VERSION 5.7 ;
  NOWIREEXTENSIONATPIN ON ;
  DIVIDERCHAR "/" ;
  BUSBITCHARS "[]" ;
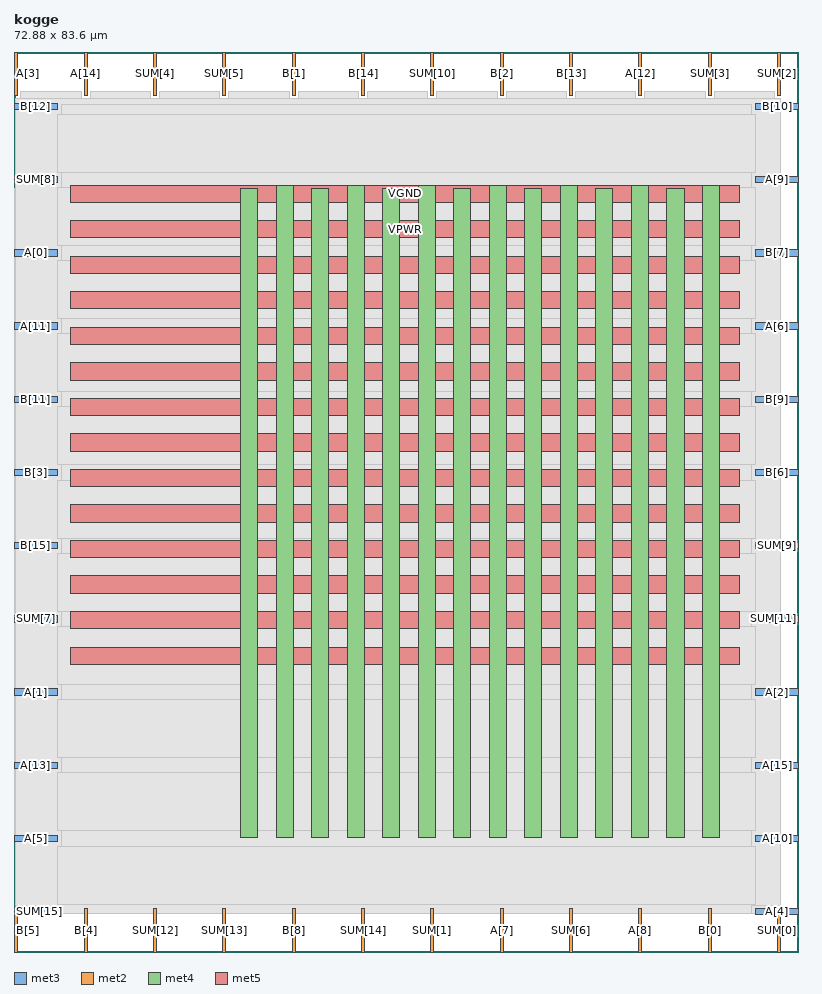
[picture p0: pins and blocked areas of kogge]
MACRO kogge
  CLASS BLOCK ;
  FOREIGN kogge ;
  ORIGIN 0.000 0.000 ;
  SIZE 72.880 BY 83.600 ;
  PIN A[0]
    DIRECTION INPUT ;
    USE SIGNAL ;
    ANTENNAGATEAREA 0.196500 ;
    PORT
      LAYER met3 ;
        RECT 0.000 64.640 4.000 65.240 ;
    END
  END A[0]
  PIN A[10]
    DIRECTION INPUT ;
    USE SIGNAL ;
    ANTENNAGATEAREA 0.213000 ;
    PORT
      LAYER met3 ;
        RECT 68.880 10.240 72.880 10.840 ;
    END
  END A[10]
  PIN A[11]
    DIRECTION INPUT ;
    USE SIGNAL ;
    ANTENNAGATEAREA 0.213000 ;
    PORT
      LAYER met3 ;
        RECT 0.000 57.840 4.000 58.440 ;
    END
  END A[11]
  PIN A[12]
    DIRECTION INPUT ;
    USE SIGNAL ;
    ANTENNAGATEAREA 0.213000 ;
    PORT
      LAYER met2 ;
        RECT 58.050 79.600 58.330 83.600 ;
    END
  END A[12]
  PIN A[13]
    DIRECTION INPUT ;
    USE SIGNAL ;
    ANTENNAGATEAREA 0.213000 ;
    PORT
      LAYER met3 ;
        RECT 0.000 17.040 4.000 17.640 ;
    END
  END A[13]
  PIN A[14]
    DIRECTION INPUT ;
    USE SIGNAL ;
    ANTENNAGATEAREA 0.196500 ;
    PORT
      LAYER met2 ;
        RECT 6.530 79.600 6.810 83.600 ;
    END
  END A[14]
  PIN A[15]
    DIRECTION INPUT ;
    USE SIGNAL ;
    ANTENNAGATEAREA 0.196500 ;
    PORT
      LAYER met3 ;
        RECT 68.880 17.040 72.880 17.640 ;
    END
  END A[15]
  PIN A[1]
    DIRECTION INPUT ;
    USE SIGNAL ;
    ANTENNAGATEAREA 0.196500 ;
    PORT
      LAYER met3 ;
        RECT 0.000 23.840 4.000 24.440 ;
    END
  END A[1]
  PIN A[2]
    DIRECTION INPUT ;
    USE SIGNAL ;
    ANTENNAGATEAREA 0.213000 ;
    PORT
      LAYER met3 ;
        RECT 68.880 23.840 72.880 24.440 ;
    END
  END A[2]
  PIN A[3]
    DIRECTION INPUT ;
    USE SIGNAL ;
    ANTENNAGATEAREA 0.213000 ;
    PORT
      LAYER met2 ;
        RECT 0.090 79.600 0.370 83.600 ;
    END
  END A[3]
  PIN A[4]
    DIRECTION INPUT ;
    USE SIGNAL ;
    ANTENNAGATEAREA 0.213000 ;
    PORT
      LAYER met3 ;
        RECT 68.880 3.440 72.880 4.040 ;
    END
  END A[4]
  PIN A[5]
    DIRECTION INPUT ;
    USE SIGNAL ;
    ANTENNAGATEAREA 0.213000 ;
    PORT
      LAYER met3 ;
        RECT 0.000 10.240 4.000 10.840 ;
    END
  END A[5]
  PIN A[6]
    DIRECTION INPUT ;
    USE SIGNAL ;
    ANTENNAGATEAREA 0.213000 ;
    PORT
      LAYER met3 ;
        RECT 68.880 57.840 72.880 58.440 ;
    END
  END A[6]
  PIN A[7]
    DIRECTION INPUT ;
    USE SIGNAL ;
    ANTENNAGATEAREA 0.213000 ;
    PORT
      LAYER met2 ;
        RECT 45.170 0.000 45.450 4.000 ;
    END
  END A[7]
  PIN A[8]
    DIRECTION INPUT ;
    USE SIGNAL ;
    ANTENNAGATEAREA 0.213000 ;
    PORT
      LAYER met2 ;
        RECT 58.050 0.000 58.330 4.000 ;
    END
  END A[8]
  PIN A[9]
    DIRECTION INPUT ;
    USE SIGNAL ;
    ANTENNAGATEAREA 0.213000 ;
    PORT
      LAYER met3 ;
        RECT 68.880 71.440 72.880 72.040 ;
    END
  END A[9]
  PIN B[0]
    DIRECTION INPUT ;
    USE SIGNAL ;
    ANTENNAGATEAREA 0.196500 ;
    PORT
      LAYER met2 ;
        RECT 64.490 0.000 64.770 4.000 ;
    END
  END B[0]
  PIN B[10]
    DIRECTION INPUT ;
    USE SIGNAL ;
    ANTENNAGATEAREA 0.213000 ;
    PORT
      LAYER met3 ;
        RECT 68.880 78.240 72.880 78.840 ;
    END
  END B[10]
  PIN B[11]
    DIRECTION INPUT ;
    USE SIGNAL ;
    ANTENNAGATEAREA 0.213000 ;
    PORT
      LAYER met3 ;
        RECT 0.000 51.040 4.000 51.640 ;
    END
  END B[11]
  PIN B[12]
    DIRECTION INPUT ;
    USE SIGNAL ;
    ANTENNAGATEAREA 0.213000 ;
    PORT
      LAYER met3 ;
        RECT 0.000 78.240 4.000 78.840 ;
    END
  END B[12]
  PIN B[13]
    DIRECTION INPUT ;
    USE SIGNAL ;
    ANTENNAGATEAREA 0.213000 ;
    PORT
      LAYER met2 ;
        RECT 51.610 79.600 51.890 83.600 ;
    END
  END B[13]
  PIN B[14]
    DIRECTION INPUT ;
    USE SIGNAL ;
    ANTENNAGATEAREA 0.196500 ;
    PORT
      LAYER met2 ;
        RECT 32.290 79.600 32.570 83.600 ;
    END
  END B[14]
  PIN B[15]
    DIRECTION INPUT ;
    USE SIGNAL ;
    ANTENNAGATEAREA 0.196500 ;
    PORT
      LAYER met3 ;
        RECT 0.000 37.440 4.000 38.040 ;
    END
  END B[15]
  PIN B[1]
    DIRECTION INPUT ;
    USE SIGNAL ;
    ANTENNAGATEAREA 0.126000 ;
    PORT
      LAYER met2 ;
        RECT 25.850 79.600 26.130 83.600 ;
    END
  END B[1]
  PIN B[2]
    DIRECTION INPUT ;
    USE SIGNAL ;
    ANTENNAGATEAREA 0.213000 ;
    PORT
      LAYER met2 ;
        RECT 45.170 79.600 45.450 83.600 ;
    END
  END B[2]
  PIN B[3]
    DIRECTION INPUT ;
    USE SIGNAL ;
    ANTENNAGATEAREA 0.213000 ;
    PORT
      LAYER met3 ;
        RECT 0.000 44.240 4.000 44.840 ;
    END
  END B[3]
  PIN B[4]
    DIRECTION INPUT ;
    USE SIGNAL ;
    ANTENNAGATEAREA 0.213000 ;
    PORT
      LAYER met2 ;
        RECT 6.530 0.000 6.810 4.000 ;
    END
  END B[4]
  PIN B[5]
    DIRECTION INPUT ;
    USE SIGNAL ;
    ANTENNAGATEAREA 0.213000 ;
    PORT
      LAYER met2 ;
        RECT 0.090 0.000 0.370 4.000 ;
    END
  END B[5]
  PIN B[6]
    DIRECTION INPUT ;
    USE SIGNAL ;
    ANTENNAGATEAREA 0.213000 ;
    PORT
      LAYER met3 ;
        RECT 68.880 44.240 72.880 44.840 ;
    END
  END B[6]
  PIN B[7]
    DIRECTION INPUT ;
    USE SIGNAL ;
    ANTENNAGATEAREA 0.213000 ;
    PORT
      LAYER met3 ;
        RECT 68.880 64.640 72.880 65.240 ;
    END
  END B[7]
  PIN B[8]
    DIRECTION INPUT ;
    USE SIGNAL ;
    ANTENNAGATEAREA 0.213000 ;
    PORT
      LAYER met2 ;
        RECT 25.850 0.000 26.130 4.000 ;
    END
  END B[8]
  PIN B[9]
    DIRECTION INPUT ;
    USE SIGNAL ;
    ANTENNAGATEAREA 0.213000 ;
    PORT
      LAYER met3 ;
        RECT 68.880 51.040 72.880 51.640 ;
    END
  END B[9]
  PIN SUM[0]
    DIRECTION OUTPUT TRISTATE ;
    USE SIGNAL ;
    ANTENNADIFFAREA 0.795200 ;
    PORT
      LAYER met2 ;
        RECT 70.930 0.000 71.210 4.000 ;
    END
  END SUM[0]
  PIN SUM[10]
    DIRECTION OUTPUT TRISTATE ;
    USE SIGNAL ;
    ANTENNADIFFAREA 0.795200 ;
    PORT
      LAYER met2 ;
        RECT 38.730 79.600 39.010 83.600 ;
    END
  END SUM[10]
  PIN SUM[11]
    DIRECTION OUTPUT TRISTATE ;
    USE SIGNAL ;
    ANTENNADIFFAREA 0.445500 ;
    PORT
      LAYER met3 ;
        RECT 68.880 30.640 72.880 31.240 ;
    END
  END SUM[11]
  PIN SUM[12]
    DIRECTION OUTPUT TRISTATE ;
    USE SIGNAL ;
    ANTENNADIFFAREA 0.795200 ;
    PORT
      LAYER met2 ;
        RECT 12.970 0.000 13.250 4.000 ;
    END
  END SUM[12]
  PIN SUM[13]
    DIRECTION OUTPUT TRISTATE ;
    USE SIGNAL ;
    ANTENNADIFFAREA 0.795200 ;
    PORT
      LAYER met2 ;
        RECT 19.410 0.000 19.690 4.000 ;
    END
  END SUM[13]
  PIN SUM[14]
    DIRECTION OUTPUT TRISTATE ;
    USE SIGNAL ;
    ANTENNADIFFAREA 0.795200 ;
    PORT
      LAYER met2 ;
        RECT 32.290 0.000 32.570 4.000 ;
    END
  END SUM[14]
  PIN SUM[15]
    DIRECTION OUTPUT TRISTATE ;
    USE SIGNAL ;
    ANTENNADIFFAREA 0.795200 ;
    PORT
      LAYER met3 ;
        RECT 0.000 3.440 4.000 4.040 ;
    END
  END SUM[15]
  PIN SUM[1]
    DIRECTION OUTPUT TRISTATE ;
    USE SIGNAL ;
    ANTENNADIFFAREA 0.795200 ;
    PORT
      LAYER met2 ;
        RECT 38.730 0.000 39.010 4.000 ;
    END
  END SUM[1]
  PIN SUM[2]
    DIRECTION OUTPUT TRISTATE ;
    USE SIGNAL ;
    ANTENNADIFFAREA 0.795200 ;
    PORT
      LAYER met2 ;
        RECT 70.930 79.600 71.210 83.600 ;
    END
  END SUM[2]
  PIN SUM[3]
    DIRECTION OUTPUT TRISTATE ;
    USE SIGNAL ;
    ANTENNADIFFAREA 0.445500 ;
    PORT
      LAYER met2 ;
        RECT 64.490 79.600 64.770 83.600 ;
    END
  END SUM[3]
  PIN SUM[4]
    DIRECTION OUTPUT TRISTATE ;
    USE SIGNAL ;
    ANTENNADIFFAREA 0.795200 ;
    PORT
      LAYER met2 ;
        RECT 12.970 79.600 13.250 83.600 ;
    END
  END SUM[4]
  PIN SUM[5]
    DIRECTION OUTPUT TRISTATE ;
    USE SIGNAL ;
    ANTENNADIFFAREA 0.795200 ;
    PORT
      LAYER met2 ;
        RECT 19.410 79.600 19.690 83.600 ;
    END
  END SUM[5]
  PIN SUM[6]
    DIRECTION OUTPUT TRISTATE ;
    USE SIGNAL ;
    ANTENNADIFFAREA 0.795200 ;
    PORT
      LAYER met2 ;
        RECT 51.610 0.000 51.890 4.000 ;
    END
  END SUM[6]
  PIN SUM[7]
    DIRECTION OUTPUT TRISTATE ;
    USE SIGNAL ;
    ANTENNADIFFAREA 0.795200 ;
    PORT
      LAYER met3 ;
        RECT 0.000 30.640 4.000 31.240 ;
    END
  END SUM[7]
  PIN SUM[8]
    DIRECTION OUTPUT TRISTATE ;
    USE SIGNAL ;
    ANTENNADIFFAREA 0.795200 ;
    PORT
      LAYER met3 ;
        RECT 0.000 71.440 4.000 72.040 ;
    END
  END SUM[8]
  PIN SUM[9]
    DIRECTION OUTPUT TRISTATE ;
    USE SIGNAL ;
    ANTENNADIFFAREA 0.445500 ;
    PORT
      LAYER met3 ;
        RECT 68.880 37.440 72.880 38.040 ;
    END
  END SUM[9]
  PIN VGND
    DIRECTION INOUT ;
    USE GROUND ;
    PORT
      LAYER met4 ;
        RECT 24.340 10.640 25.940 71.230 ;
    END
    PORT
      LAYER met4 ;
        RECT 30.940 10.640 32.540 71.230 ;
    END
    PORT
      LAYER met4 ;
        RECT 37.540 10.640 39.140 71.230 ;
    END
    PORT
      LAYER met4 ;
        RECT 44.140 10.640 45.740 71.230 ;
    END
    PORT
      LAYER met4 ;
        RECT 50.740 10.640 52.340 71.230 ;
    END
    PORT
      LAYER met4 ;
        RECT 57.340 10.640 58.940 71.230 ;
    END
    PORT
      LAYER met4 ;
        RECT 63.940 10.640 65.540 71.230 ;
    END
    PORT
      LAYER met5 ;
        RECT 5.280 30.030 67.400 31.630 ;
    END
    PORT
      LAYER met5 ;
        RECT 5.280 36.630 67.400 38.230 ;
    END
    PORT
      LAYER met5 ;
        RECT 5.280 43.230 67.400 44.830 ;
    END
    PORT
      LAYER met5 ;
        RECT 5.280 49.830 67.400 51.430 ;
    END
    PORT
      LAYER met5 ;
        RECT 5.280 56.430 67.400 58.030 ;
    END
    PORT
      LAYER met5 ;
        RECT 5.280 63.030 67.400 64.630 ;
    END
    PORT
      LAYER met5 ;
        RECT 5.280 69.630 67.400 71.230 ;
    END
  END VGND
  PIN VPWR
    DIRECTION INOUT ;
    USE POWER ;
    PORT
      LAYER met4 ;
        RECT 21.040 10.640 22.640 70.960 ;
    END
    PORT
      LAYER met4 ;
        RECT 27.640 10.640 29.240 70.960 ;
    END
    PORT
      LAYER met4 ;
        RECT 34.240 10.640 35.840 70.960 ;
    END
    PORT
      LAYER met4 ;
        RECT 40.840 10.640 42.440 70.960 ;
    END
    PORT
      LAYER met4 ;
        RECT 47.440 10.640 49.040 70.960 ;
    END
    PORT
      LAYER met4 ;
        RECT 54.040 10.640 55.640 70.960 ;
    END
    PORT
      LAYER met4 ;
        RECT 60.640 10.640 62.240 70.960 ;
    END
    PORT
      LAYER met5 ;
        RECT 5.280 26.730 67.400 28.330 ;
    END
    PORT
      LAYER met5 ;
        RECT 5.280 33.330 67.400 34.930 ;
    END
    PORT
      LAYER met5 ;
        RECT 5.280 39.930 67.400 41.530 ;
    END
    PORT
      LAYER met5 ;
        RECT 5.280 46.530 67.400 48.130 ;
    END
    PORT
      LAYER met5 ;
        RECT 5.280 53.130 67.400 54.730 ;
    END
    PORT
      LAYER met5 ;
        RECT 5.280 59.730 67.400 61.330 ;
    END
    PORT
      LAYER met5 ;
        RECT 5.280 66.330 67.400 67.930 ;
    END
  END VPWR
  OBS
      LAYER li1 ;
        RECT 5.520 10.795 67.160 70.805 ;
      LAYER met1 ;
        RECT 0.070 10.640 71.230 70.960 ;
      LAYER met2 ;
        RECT 0.650 79.320 6.250 79.970 ;
        RECT 7.090 79.320 12.690 79.970 ;
        RECT 13.530 79.320 19.130 79.970 ;
        RECT 19.970 79.320 25.570 79.970 ;
        RECT 26.410 79.320 32.010 79.970 ;
        RECT 32.850 79.320 38.450 79.970 ;
        RECT 39.290 79.320 44.890 79.970 ;
        RECT 45.730 79.320 51.330 79.970 ;
        RECT 52.170 79.320 57.770 79.970 ;
        RECT 58.610 79.320 64.210 79.970 ;
        RECT 65.050 79.320 70.650 79.970 ;
        RECT 0.100 4.280 71.200 79.320 ;
        RECT 0.650 3.555 6.250 4.280 ;
        RECT 7.090 3.555 12.690 4.280 ;
        RECT 13.530 3.555 19.130 4.280 ;
        RECT 19.970 3.555 25.570 4.280 ;
        RECT 26.410 3.555 32.010 4.280 ;
        RECT 32.850 3.555 38.450 4.280 ;
        RECT 39.290 3.555 44.890 4.280 ;
        RECT 45.730 3.555 51.330 4.280 ;
        RECT 52.170 3.555 57.770 4.280 ;
        RECT 58.610 3.555 64.210 4.280 ;
        RECT 65.050 3.555 70.650 4.280 ;
      LAYER met3 ;
        RECT 4.400 77.840 68.480 78.705 ;
        RECT 4.000 72.440 68.880 77.840 ;
        RECT 4.400 71.040 68.480 72.440 ;
        RECT 4.000 65.640 68.880 71.040 ;
        RECT 4.400 64.240 68.480 65.640 ;
        RECT 4.000 58.840 68.880 64.240 ;
        RECT 4.400 57.440 68.480 58.840 ;
        RECT 4.000 52.040 68.880 57.440 ;
        RECT 4.400 50.640 68.480 52.040 ;
        RECT 4.000 45.240 68.880 50.640 ;
        RECT 4.400 43.840 68.480 45.240 ;
        RECT 4.000 38.440 68.880 43.840 ;
        RECT 4.400 37.040 68.480 38.440 ;
        RECT 4.000 31.640 68.880 37.040 ;
        RECT 4.400 30.240 68.480 31.640 ;
        RECT 4.000 24.840 68.880 30.240 ;
        RECT 4.400 23.440 68.480 24.840 ;
        RECT 4.000 18.040 68.880 23.440 ;
        RECT 4.400 16.640 68.480 18.040 ;
        RECT 4.000 11.240 68.880 16.640 ;
        RECT 4.400 9.840 68.480 11.240 ;
        RECT 4.000 4.440 68.880 9.840 ;
        RECT 4.400 3.575 68.480 4.440 ;
  END
END kogge
END LIBRARY

